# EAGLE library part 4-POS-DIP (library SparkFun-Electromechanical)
4 Position DIP Switch CTS series 219

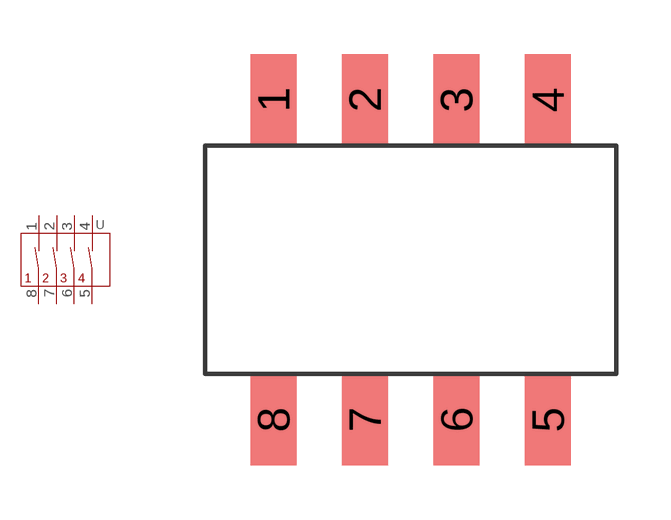
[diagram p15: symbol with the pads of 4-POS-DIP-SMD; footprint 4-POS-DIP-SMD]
Designator prefix -

## 4-POS-DIP (PROD_ID: SWCH-12418)  [4-POS-DIP-SMD]
1  1A
2  2A
3  3A
4  4A
5  4B
6  3B
7  2B
8  1B

## Footprint 4-POS-DIP-SMD (pad centres in mm)
smd 1.27 x 2.54: 1 -3.81,4.445; 2 -1.27,4.445; 3 1.27,4.445; 4 3.81,4.445; 5 3.81,-4.445; 6 1.27,-4.445; 7 -1.27,-4.445; 8 -3.81,-4.445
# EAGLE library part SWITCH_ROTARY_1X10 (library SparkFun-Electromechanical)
SWCH-12120

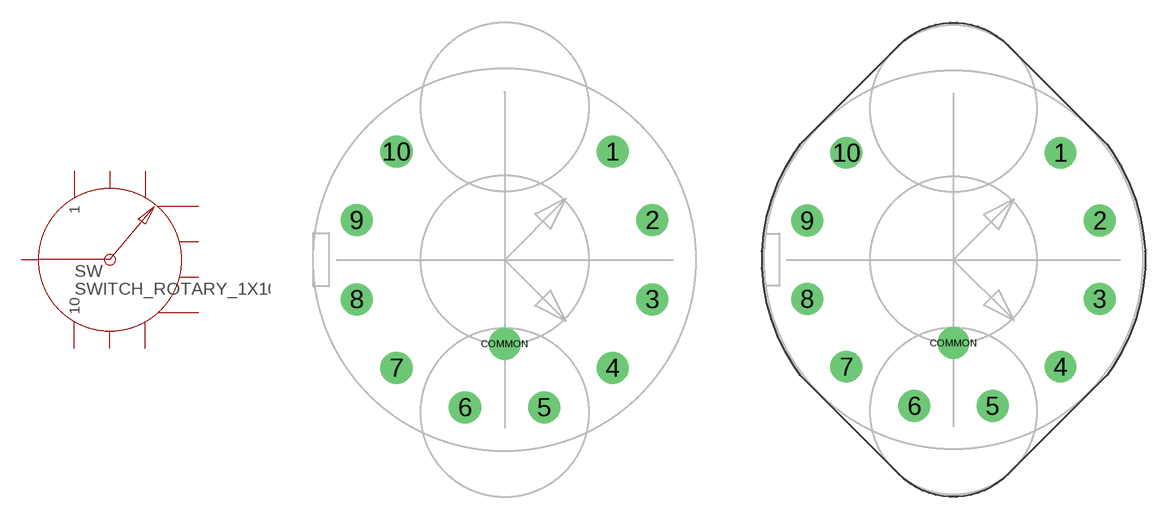
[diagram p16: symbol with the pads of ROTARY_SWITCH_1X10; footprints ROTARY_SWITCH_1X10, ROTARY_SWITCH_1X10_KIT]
Designator prefix SW

## SWITCH_ROTARY_1X10 (PROD_ID: SWCH-12120; VALUE: 1x10)  [ROTARY_SWITCH_1X10]
1  1
2  2
3  3
4  4
5  5
6  6
7  7
8  8
9  9
10  10
COMMON  COMMON

## SWITCH_ROTARY_1X10KIT (PROD_ID: SWCH-12120; VALUE: 1x10)  [ROTARY_SWITCH_1X10_KIT]
Pads as for ROTARY_SWITCH_1X10

## Footprint ROTARY_SWITCH_1X10 (pad centres in mm)
Taiwan Alpha 1 pole, 10 pos rotary switch Alpha PN SR2512F-0110-16f2b-c9-s-k Arrows in tDocu denote pointer positions for 45-degree shaft, assuming a knob with a pointer that's opposite the set screw.
drill 1.4: 1 7.071,7.071; 2 9.659,2.588; 3 9.659,-2.588; 4 7.071,-7.071; 5 2.588,-9.659; 6 -2.588,-9.659; 7 -7.071,-7.071; 8 -9.659,-2.588; 9 -9.659,2.588; 10 -7.071,7.071; COMMON 0,-5.5

## Footprint ROTARY_SWITCH_1X10_KIT (pad centres in mm)
drill 1.4: 1 7.071,7.071; 2 9.659,2.588; 3 9.659,-2.588; 4 7.071,-7.071; 5 2.588,-9.659; 6 -2.588,-9.659; 7 -7.071,-7.071; 8 -9.659,-2.588; 9 -9.659,2.588; 10 -7.071,7.071; COMMON 0,-5.5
